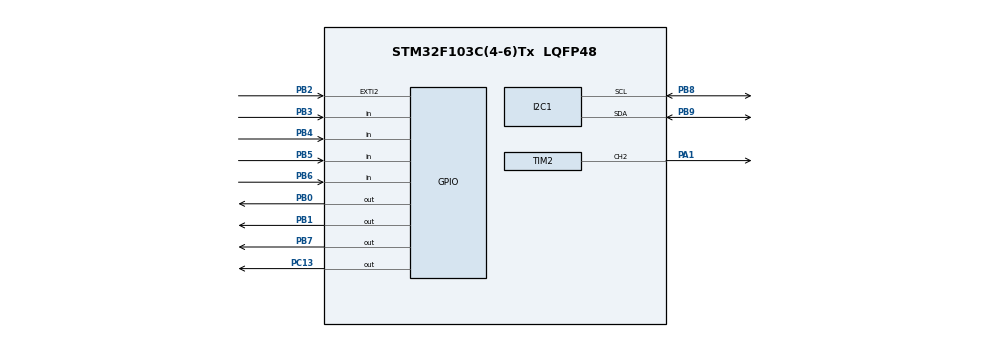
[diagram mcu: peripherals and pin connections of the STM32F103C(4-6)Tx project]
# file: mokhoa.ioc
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FREERTOS.Tasks01=defaultTask,0,128,StartDefaultTask,Default,NULL,Dynamic,NULL,NULL;Task01,0,128,StartTask01,Default,NULL,Dynamic,NULL,NULL;Task02,0,128,StartTask02,Default,NULL,Dynamic,NULL,NULL;Task03,0,128,StartTask03,Default,NULL,Dynamic,NULL,NULL
Mcu.Family=STM32F1
Mcu.Name=STM32F103C(4-6)Tx
Mcu.Package=LQFP48
NVIC.PriorityGroup=NVIC_PRIORITYGROUP_4
PA1.Signal=S_TIM2_CH2
PA13.Mode=Serial_Wire
PA13.Signal=SYS_JTMS-SWDIO
PA14.Mode=Serial_Wire
PA14.Signal=SYS_JTCK-SWCLK
PB0.PinState=GPIO_PIN_SET
PB0.Signal=GPIO_Output
PB1.PinState=GPIO_PIN_SET
PB1.Signal=GPIO_Output
PB2.Signal=GPXTI2
PB3.GPIO_PuPd=GPIO_PULLUP
PB3.Signal=GPIO_Input
PB4.GPIO_PuPd=GPIO_PULLUP
PB4.Signal=GPIO_Input
PB5.GPIO_PuPd=GPIO_PULLUP
PB5.Signal=GPIO_Input
PB6.GPIO_PuPd=GPIO_PULLUP
PB6.Signal=GPIO_Input
PB7.PinState=GPIO_PIN_SET
PB7.Signal=GPIO_Output
PB8.Mode=I2C
PB8.Signal=I2C1_SCL
PB9.Mode=I2C
PB9.Signal=I2C1_SDA
PC13-TAMPER-RTC.Signal=GPIO_Output
PD0-OSC_IN.Mode=HSE-External-Oscillator
PD0-OSC_IN.Signal=RCC_OSC_IN
PD1-OSC_OUT.Mode=HSE-External-Oscillator
PD1-OSC_OUT.Signal=RCC_OSC_OUT
ProjectManager.HeapSize=0x200
ProjectManager.StackSize=0x400
ProjectManager.TargetToolchain=MDK-ARM V5
RCC.APB1Freq_Value=8000000
RCC.APB2Freq_Value=8000000
SH.S_TIM2_CH2.0=TIM2_CH2,PWM Generation2 CH2
TIM2.Channel-PWM\ Generation2\ CH2=TIM_CHANNEL_2
TIM2.Period=9999
TIM2.Prescaler=15
VP_FREERTOS_VS_CMSIS_V1.Mode=CMSIS_V1
VP_TIM2_VS_ClockSourceINT.Mode=Internal
board=custom

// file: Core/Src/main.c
/* USER CODE BEGIN Header */
/**
  ******************************************************************************
  * @file           : main.c
  * @brief          : Main program body
  ******************************************************************************
  * @attention
  *
  * Copyright (c) 2023 STMicroelectronics.
  * All rights reserved.
  *
  * This software is licensed under terms that can be found in the LICENSE file
  * in the root directory of this software component.
  * If no LICENSE file comes with this software, it is provided AS-IS.
  *
  ******************************************************************************
  */
/* USER CODE END Header */
#include "main.h"
#include "cmsis_os.h"

/* USER CODE BEGIN Includes */
#include "i2c-lcd.h"
#include "stdio.h"
/* USER CODE END Includes */

I2C_HandleTypeDef hi2c1;

TIM_HandleTypeDef htim2;

osThreadId defaultTaskHandle;
osThreadId Task01Handle;
osThreadId Task02Handle;
osThreadId Task03Handle;
/* USER CODE BEGIN PV */
int my_array[5];
int my_array[5] = {1, 4, 0, 4, 9};

uint8_t dem = 0;
char var[8];
//uint8_t var[8];
char password[8] = {'1','1','1','1','1','1','1','1'};
uint8_t Nhapsai = 0;
/* USER CODE END PV */

void SystemClock_Config(void);
static void MX_GPIO_Init(void);
static void MX_I2C1_Init(void);
static void MX_TIM2_Init(void);
void StartDefaultTask(void const * argument);
void StartTask01(void const * argument);
void StartTask02(void const * argument);
void StartTask03(void const * argument);

/* USER CODE BEGIN 0 */
void CheckPass(void)
{
	if(Nhapsai<3)
	{
		for(int k=0;k<8;k++)
		if(var[k] == password[k])
		{
			if(k == 7)
			{

				for(int i=0;i<8;i++)
				var[i]= ' ';
				dem=0;
				lcd_put_cur(2,0);
				lcd_send_string("OKE");

				HAL_TIM_PWM_Start (&htim2, TIM_CHANNEL_2);
				__HAL_TIM_SET_COMPARE(&htim2, TIM_CHANNEL_2, 250);
				HAL_GPIO_WritePin(GPIOC,GPIO_PIN_13,1);
				HAL_Delay(5000);
				__HAL_TIM_SET_COMPARE(&htim2, TIM_CHANNEL_2, 750);
				HAL_GPIO_WritePin(GPIOC,GPIO_PIN_13,0);
				lcd_put_cur(2,0);
				lcd_send_string("          ");
				Nhapsai =0;
				HAL_Delay(2000);

			}
		}
		else
		{
				for(int j=0;j<8;j++)
				var[j] = ' ';
				dem=0;
				lcd_put_cur(2,0);
				lcd_send_string("SAI");

				HAL_Delay(500);
				lcd_put_cur(2,0);
				lcd_send_string("   ");

		}
	}
	Nhapsai++;
}

void quetbanphim()
{
	HAL_GPIO_WritePin(GPIOB,GPIO_PIN_0,0);
	if(HAL_GPIO_ReadPin(GPIOB,GPIO_PIN_3)==0)                // nhan phim 1
		{
			while(HAL_GPIO_ReadPin(GPIOB,GPIO_PIN_3)==0){}
			if(dem<8)
			{
				var[dem] = '1';
				dem++;
			}
		}
	if(HAL_GPIO_ReadPin(GPIOB,GPIO_PIN_4)==0)                // nhan phim 4
		{
			while(HAL_GPIO_ReadPin(GPIOB,GPIO_PIN_4)==0){}
			if(dem<8)
			{
				var[dem] = '4';
				dem++;
			}
		}
	if(HAL_GPIO_ReadPin(GPIOB,GPIO_PIN_5)==0)                // nhan phim 7
		{
			while(HAL_GPIO_ReadPin(GPIOB,GPIO_PIN_5)==0){}
			if(dem<8)
			{
				var[dem] = '7';
				dem++;
			}
		}
	if(HAL_GPIO_ReadPin(GPIOB,GPIO_PIN_6)==0)                // nhan phim * hay phim xoa
		{

			while(HAL_GPIO_ReadPin(GPIOB,GPIO_PIN_6)==0){}
  			if(dem>0)
			{
					dem--;
					var[dem]=' ';
			}

		}
  HAL_GPIO_WritePin(GPIOB,GPIO_PIN_0,1);
	// nhan cot thu hai
	HAL_GPIO_WritePin(GPIOB,GPIO_PIN_1,0);
	if(HAL_GPIO_ReadPin(GPIOB,GPIO_PIN_3)==0)                // nhan phim 2
		{
			while(HAL_GPIO_ReadPin(GPIOB,GPIO_PIN_3)==0){}
			if(dem<8)
			{
				var[dem] = '2';
				dem++;
			}
		}
	if(HAL_GPIO_ReadPin(GPIOB,GPIO_PIN_4)==0)                // nhan phim 5
		{
			while(HAL_GPIO_ReadPin(GPIOB,GPIO_PIN_4)==0){}
			if(dem<8)
			{
				var[dem] = '5';
				dem++;
			}
		}
	if(HAL_GPIO_ReadPin(GPIOB,GPIO_PIN_5)==0)                // nhan phim 8
		{
			while(HAL_GPIO_ReadPin(GPIOB,GPIO_PIN_5)==0){}
			if(dem<8)
			{
				var[dem] = '8';
				dem++;
			}
		}
	if(HAL_GPIO_ReadPin(GPIOB,GPIO_PIN_6)==0)                // nhan phim 0
		{
			while(HAL_GPIO_ReadPin(GPIOB,GPIO_PIN_6)==0){}
			if(dem<8)
			{
				var[dem] = '0';
				dem++;
			}
		}
	HAL_GPIO_WritePin(GPIOB,GPIO_PIN_1,1);
	// nhan cot thu ba
	HAL_GPIO_WritePin(GPIOB,GPIO_PIN_7,0);
	if(HAL_GPIO_ReadPin(GPIOB,GPIO_PIN_3)==0)                // nhan phim 3
		{
			while(HAL_GPIO_ReadPin(GPIOB,GPIO_PIN_3)==0){}
			if(dem<8)
			{
				var[dem] = '3';
				dem++;
			}
		}
	if(HAL_GPIO_ReadPin(GPIOB,GPIO_PIN_4)==0)                // nhan phim 6
		{
			while(HAL_GPIO_ReadPin(GPIOB,GPIO_PIN_4)==0){}
			if(dem<8)
			{
				var[dem] = '6';
				dem++;
			}
		}
	if(HAL_GPIO_ReadPin(GPIOB,GPIO_PIN_5)==0)                // nhan phim 9
		{
			while(HAL_GPIO_ReadPin(GPIOB,GPIO_PIN_5)==0){}
			if(dem<8)
			{
				var[dem] = '9';
				dem++;
			}
		}
	if(HAL_GPIO_ReadPin(GPIOB,GPIO_PIN_6)==0)                // nhan phim # hay phim Enter
		{
			while(HAL_GPIO_ReadPin(GPIOB,GPIO_PIN_6)==0){}
//			for(int i=0;i<8;i++){
//				var[i]=' ';
//			}
			CheckPass();                                         // kiem tra mat khau
		}
	HAL_GPIO_WritePin(GPIOB,GPIO_PIN_7,1);
}

/* USER CODE END 0 */

int main(void)
{

  /* MCU Configuration--------------------------------------------------------*/

  /* Reset of all peripherals, Initializes the Flash interface and the Systick. */
  HAL_Init();

  /* Configure the system clock */
  SystemClock_Config();

  /* Initialize all configured peripherals */
  MX_GPIO_Init();
  MX_I2C1_Init();
  MX_TIM2_Init();
	lcd_init(); //initialize lcd

	lcd_put_cur(0, 1);
	lcd_send_string(" Nhap Mat Ma");

  /* Create the thread(s) */
  /* definition and creation of defaultTask */
  osThreadDef(defaultTask, StartDefaultTask, osPriorityNormal, 0, 128);
  defaultTaskHandle = osThreadCreate(osThread(defaultTask), NULL);

  /* definition and creation of Task01 */
  osThreadDef(Task01, StartTask01, osPriorityNormal, 0, 128);
  Task01Handle = osThreadCreate(osThread(Task01), NULL);

  /* definition and creation of Task02 */
  osThreadDef(Task02, StartTask02, osPriorityNormal, 0, 128);
  Task02Handle = osThreadCreate(osThread(Task02), NULL);

  /* definition and creation of Task03 */
  osThreadDef(Task03, StartTask03, osPriorityNormal, 0, 128);
  Task03Handle = osThreadCreate(osThread(Task03), NULL);

  /* Start scheduler */
  osKernelStart();
  /* We should never get here as control is now taken by the scheduler */
  /* Infinite loop */
  while (1)
  {

    /* USER CODE BEGIN 3 */

		//quetled();
  }
  /* USER CODE END 3 */
}

void SystemClock_Config(void)
{
  RCC_OscInitTypeDef RCC_OscInitStruct = {0};
  RCC_ClkInitTypeDef RCC_ClkInitStruct = {0};

  /** Initializes the RCC Oscillators according to the specified parameters
  * in the RCC_OscInitTypeDef structure.
  */
  RCC_OscInitStruct.OscillatorType = RCC_OSCILLATORTYPE_HSI;
  RCC_OscInitStruct.HSIState = RCC_HSI_ON;
  RCC_OscInitStruct.HSICalibrationValue = RCC_HSICALIBRATION_DEFAULT;
  RCC_OscInitStruct.PLL.PLLState = RCC_PLL_NONE;
  if (HAL_RCC_OscConfig(&RCC_OscInitStruct) != HAL_OK)
  {
    Error_Handler();
  }

  /** Initializes the CPU, AHB and APB buses clocks
  */
  RCC_ClkInitStruct.ClockType = RCC_CLOCKTYPE_HCLK|RCC_CLOCKTYPE_SYSCLK
                              |RCC_CLOCKTYPE_PCLK1|RCC_CLOCKTYPE_PCLK2;
  RCC_ClkInitStruct.SYSCLKSource = RCC_SYSCLKSOURCE_HSI;
  RCC_ClkInitStruct.AHBCLKDivider = RCC_SYSCLK_DIV1;
  RCC_ClkInitStruct.APB1CLKDivider = RCC_HCLK_DIV1;
  RCC_ClkInitStruct.APB2CLKDivider = RCC_HCLK_DIV1;

  if (HAL_RCC_ClockConfig(&RCC_ClkInitStruct, FLASH_LATENCY_0) != HAL_OK)
  {
    Error_Handler();
  }
}

static void MX_I2C1_Init(void)
{

  hi2c1.Instance = I2C1;
  hi2c1.Init.ClockSpeed = 100000;
  hi2c1.Init.DutyCycle = I2C_DUTYCYCLE_2;
  hi2c1.Init.OwnAddress1 = 0;
  hi2c1.Init.AddressingMode = I2C_ADDRESSINGMODE_7BIT;
  hi2c1.Init.DualAddressMode = I2C_DUALADDRESS_DISABLE;
  hi2c1.Init.OwnAddress2 = 0;
  hi2c1.Init.GeneralCallMode = I2C_GENERALCALL_DISABLE;
  hi2c1.Init.NoStretchMode = I2C_NOSTRETCH_DISABLE;
  if (HAL_I2C_Init(&hi2c1) != HAL_OK)
  {
    Error_Handler();
  }

}

static void MX_TIM2_Init(void)
{

  TIM_ClockConfigTypeDef sClockSourceConfig = {0};
  TIM_MasterConfigTypeDef sMasterConfig = {0};
  TIM_OC_InitTypeDef sConfigOC = {0};

  htim2.Instance = TIM2;
  htim2.Init.Prescaler = 15;
  htim2.Init.CounterMode = TIM_COUNTERMODE_UP;
  htim2.Init.Period = 9999;
  htim2.Init.ClockDivision = TIM_CLOCKDIVISION_DIV1;
  htim2.Init.AutoReloadPreload = TIM_AUTORELOAD_PRELOAD_DISABLE;
  if (HAL_TIM_Base_Init(&htim2) != HAL_OK)
  {
    Error_Handler();
  }
  sClockSourceConfig.ClockSource = TIM_CLOCKSOURCE_INTERNAL;
  if (HAL_TIM_ConfigClockSource(&htim2, &sClockSourceConfig) != HAL_OK)
  {
    Error_Handler();
  }
  if (HAL_TIM_PWM_Init(&htim2) != HAL_OK)
  {
    Error_Handler();
  }
  sMasterConfig.MasterOutputTrigger = TIM_TRGO_RESET;
  sMasterConfig.MasterSlaveMode = TIM_MASTERSLAVEMODE_DISABLE;
  if (HAL_TIMEx_MasterConfigSynchronization(&htim2, &sMasterConfig) != HAL_OK)
  {
    Error_Handler();
  }
  sConfigOC.OCMode = TIM_OCMODE_PWM1;
  sConfigOC.Pulse = 0;
  sConfigOC.OCPolarity = TIM_OCPOLARITY_HIGH;
  sConfigOC.OCFastMode = TIM_OCFAST_DISABLE;
  if (HAL_TIM_PWM_ConfigChannel(&htim2, &sConfigOC, TIM_CHANNEL_2) != HAL_OK)
  {
    Error_Handler();
  }
  HAL_TIM_MspPostInit(&htim2);

}

static void MX_GPIO_Init(void)
{
  GPIO_InitTypeDef GPIO_InitStruct = {0};

  /* GPIO Ports Clock Enable */
  __HAL_RCC_GPIOC_CLK_ENABLE();
  __HAL_RCC_GPIOD_CLK_ENABLE();
  __HAL_RCC_GPIOA_CLK_ENABLE();
  __HAL_RCC_GPIOB_CLK_ENABLE();

  /*Configure GPIO pin Output Level */
  HAL_GPIO_WritePin(GPIOC, GPIO_PIN_13, GPIO_PIN_RESET);

  /*Configure GPIO pin Output Level */
  HAL_GPIO_WritePin(GPIOB, GPIO_PIN_0|GPIO_PIN_1|GPIO_PIN_7, GPIO_PIN_SET);
	HAL_GPIO_WritePin(GPIOA, GPIO_PIN_5, GPIO_PIN_RESET);
  /*Configure GPIO pin : PC13 */
  GPIO_InitStruct.Pin = GPIO_PIN_13;
  GPIO_InitStruct.Mode = GPIO_MODE_OUTPUT_PP;
  GPIO_InitStruct.Pull = GPIO_NOPULL;
  GPIO_InitStruct.Speed = GPIO_SPEED_FREQ_LOW;
  HAL_GPIO_Init(GPIOC, &GPIO_InitStruct);

  /*Configure GPIO pins : PB0 PB1 PB7 */
  GPIO_InitStruct.Pin = GPIO_PIN_0|GPIO_PIN_1|GPIO_PIN_7;
  GPIO_InitStruct.Mode = GPIO_MODE_OUTPUT_PP;
  GPIO_InitStruct.Pull = GPIO_NOPULL;
  GPIO_InitStruct.Speed = GPIO_SPEED_FREQ_LOW;
  HAL_GPIO_Init(GPIOB, &GPIO_InitStruct);

  /*Configure GPIO pin : PB2 */
  GPIO_InitStruct.Pin = GPIO_PIN_2;
  GPIO_InitStruct.Mode = GPIO_MODE_IT_RISING;
  GPIO_InitStruct.Pull = GPIO_NOPULL;
  HAL_GPIO_Init(GPIOB, &GPIO_InitStruct);

  /*Configure GPIO pins : PB3 PB4 PB5 PB6 */
  GPIO_InitStruct.Pin = GPIO_PIN_3|GPIO_PIN_4|GPIO_PIN_5|GPIO_PIN_6;
  GPIO_InitStruct.Mode = GPIO_MODE_INPUT;
  GPIO_InitStruct.Pull = GPIO_PULLUP;
  HAL_GPIO_Init(GPIOB, &GPIO_InitStruct);

	/*Configure GPIO pin : PA0 */
  GPIO_InitStruct.Pin = GPIO_PIN_0;
  GPIO_InitStruct.Mode = GPIO_MODE_INPUT;
  GPIO_InitStruct.Pull = GPIO_PULLUP;
  HAL_GPIO_Init(GPIOA, &GPIO_InitStruct);

  /*Configure GPIO pin : PA1 */
  GPIO_InitStruct.Pin = GPIO_PIN_5;
  GPIO_InitStruct.Mode = GPIO_MODE_OUTPUT_PP;
  GPIO_InitStruct.Pull = GPIO_NOPULL;
  GPIO_InitStruct.Speed = GPIO_SPEED_FREQ_LOW;
  HAL_GPIO_Init(GPIOA, &GPIO_InitStruct);
}

void StartDefaultTask(void const * argument)
{
  /* USER CODE BEGIN 5 */
  /* Infinite loop */
  for(;;)
  {
		quetbanphim();
		for (int i = 0; i < 8; i++) {
		char buffer[16];
		sprintf(buffer, "%c", var[i]);
		lcd_put_cur(1, i);
		lcd_send_string(buffer);
		}
    osDelay(1);
  }
  /* USER CODE END 5 */
}

void StartTask01(void const * argument)
{
  /* USER CODE BEGIN StartTask01 */
  /* Infinite loop */
  for(;;)
  {
		if(HAL_GPIO_ReadPin(GPIOA,GPIO_PIN_0)==1){
		HAL_GPIO_WritePin(GPIOA,GPIO_PIN_5,1);
	}
	else
		HAL_GPIO_WritePin(GPIOA,GPIO_PIN_5,0);
    osDelay(1);
  }
  /* USER CODE END StartTask01 */
}

void StartTask02(void const * argument)
{
  for(;;)
  {
    osDelay(1);
  }
}

void StartTask03(void const * argument)
{
  for(;;)
  {
    osDelay(1);
  }
}

void Error_Handler(void)
{
  __disable_irq();
  while (1)
  {
  }
}
